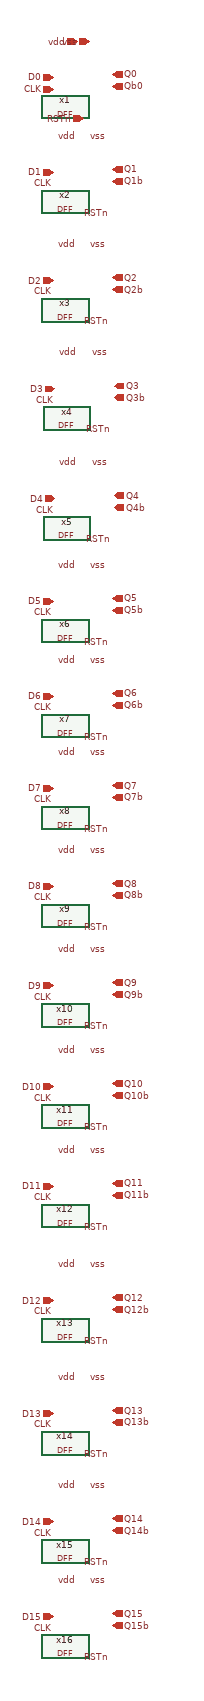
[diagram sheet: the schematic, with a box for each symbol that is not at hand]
v {xschem version=3.4.7 file_version=1.2}
G {}
K {}
V {}
S {}
E {}
C {schematics/PC/DFF/DFF.sym} 0 20 0 0 {name=x1}
C {schematics/PC/DFF/DFF.sym} 0 180 0 0 {name=x2}
C {iopin.sym} 20 -90 3 0 {name=p9 lab=vdd}
C {lab_wire.sym} 40 70 2 0 {name=p35 sig_type=std_logic lab=vss}
C {iopin.sym} 40 -90 3 0 {name=p19 lab=vss}
C {ipin.sym} 30 40 2 0 {name=p4 lab=RSTn}
C {ipin.sym} -20 -10 0 0 {name=p41 lab=CLK}
C {opin.sym} 80 -35 0 0 {name=p2 lab=Q0}
C {opin.sym} 80 -15 0 0 {name=p1 lab=Qb0}
C {ipin.sym} -20 -30 0 0 {name=p3 lab=D0}
C {opin.sym} 80 125 0 0 {name=p5 lab=Q1}
C {opin.sym} 80 145 0 0 {name=p6 lab=Q1b}
C {ipin.sym} -20 130 0 0 {name=p7 lab=D1}
C {lab_wire.sym} -20 150 0 0 {name=p11 sig_type=std_logic lab=CLK}
C {lab_wire.sym} 20 70 0 0 {name=p8 sig_type=std_logic lab=vdd}
C {lab_wire.sym} 30 200 2 0 {name=p10 sig_type=std_logic lab=RSTn}
C {schematics/PC/DFF/DFF.sym} 0 362.5 0 0 {name=x3}
C {lab_wire.sym} 40 252.5 2 0 {name=p12 sig_type=std_logic lab=vss}
C {opin.sym} 80 307.5 0 0 {name=p13 lab=Q2}
C {opin.sym} 80 327.5 0 0 {name=p14 lab=Q2b}
C {ipin.sym} -20 312.5 0 0 {name=p15 lab=D2}
C {lab_wire.sym} -20 332.5 0 0 {name=p16 sig_type=std_logic lab=CLK}
C {lab_wire.sym} 20 252.5 0 0 {name=p17 sig_type=std_logic lab=vdd}
C {lab_wire.sym} 30 382.5 2 0 {name=p18 sig_type=std_logic lab=RSTn}
C {schematics/PC/DFF/DFF.sym} 2.5 545 0 0 {name=x4}
C {lab_wire.sym} 42.5 435 2 0 {name=p20 sig_type=std_logic lab=vss}
C {opin.sym} 82.5 490 0 0 {name=p21 lab=Q3}
C {opin.sym} 82.5 510 0 0 {name=p22 lab=Q3b}
C {ipin.sym} -17.5 495 0 0 {name=p23 lab=D3}
C {lab_wire.sym} -17.5 515 0 0 {name=p24 sig_type=std_logic lab=CLK}
C {lab_wire.sym} 22.5 435 0 0 {name=p25 sig_type=std_logic lab=vdd}
C {lab_wire.sym} 32.5 565 2 0 {name=p26 sig_type=std_logic lab=RSTn}
C {schematics/PC/DFF/DFF.sym} 2.5 730 0 0 {name=x5}
C {lab_wire.sym} 42.5 620 2 0 {name=p27 sig_type=std_logic lab=vss}
C {opin.sym} 82.5 675 0 0 {name=p28 lab=Q4}
C {opin.sym} 82.5 695 0 0 {name=p29 lab=Q4b}
C {ipin.sym} -17.5 680 0 0 {name=p30 lab=D4}
C {lab_wire.sym} -17.5 700 0 0 {name=p31 sig_type=std_logic lab=CLK}
C {lab_wire.sym} 22.5 620 0 0 {name=p32 sig_type=std_logic lab=vdd}
C {lab_wire.sym} 32.5 750 2 0 {name=p33 sig_type=std_logic lab=RSTn}
C {schematics/PC/DFF/DFF.sym} 0 902.5 0 0 {name=x6}
C {lab_wire.sym} 40 792.5 2 0 {name=p34 sig_type=std_logic lab=vss}
C {opin.sym} 80 847.5 0 0 {name=p36 lab=Q5}
C {opin.sym} 80 867.5 0 0 {name=p37 lab=Q5b}
C {ipin.sym} -20 852.5 0 0 {name=p38 lab=D5}
C {lab_wire.sym} -20 872.5 0 0 {name=p39 sig_type=std_logic lab=CLK}
C {lab_wire.sym} 20 792.5 0 0 {name=p40 sig_type=std_logic lab=vdd}
C {lab_wire.sym} 30 922.5 2 0 {name=p42 sig_type=std_logic lab=RSTn}
C {schematics/PC/DFF/DFF.sym} 0 1062.5 0 0 {name=x7}
C {lab_wire.sym} 40 952.5 2 0 {name=p43 sig_type=std_logic lab=vss}
C {opin.sym} 80 1007.5 0 0 {name=p44 lab=Q6}
C {opin.sym} 80 1027.5 0 0 {name=p45 lab=Q6b}
C {ipin.sym} -20 1012.5 0 0 {name=p46 lab=D6}
C {lab_wire.sym} -20 1032.5 0 0 {name=p47 sig_type=std_logic lab=CLK}
C {lab_wire.sym} 20 952.5 0 0 {name=p48 sig_type=std_logic lab=vdd}
C {lab_wire.sym} 30 1082.5 2 0 {name=p49 sig_type=std_logic lab=RSTn}
C {schematics/PC/DFF/DFF.sym} 0 1217.5 0 0 {name=x8}
C {lab_wire.sym} 40 1107.5 2 0 {name=p50 sig_type=std_logic lab=vss}
C {opin.sym} 80 1162.5 0 0 {name=p51 lab=Q7}
C {opin.sym} 80 1182.5 0 0 {name=p52 lab=Q7b}
C {ipin.sym} -20 1167.5 0 0 {name=p53 lab=D7}
C {lab_wire.sym} -20 1187.5 0 0 {name=p54 sig_type=std_logic lab=CLK}
C {lab_wire.sym} 20 1107.5 0 0 {name=p55 sig_type=std_logic lab=vdd}
C {lab_wire.sym} 30 1237.5 2 0 {name=p56 sig_type=std_logic lab=RSTn}
C {schematics/PC/DFF/DFF.sym} 0 1382.5 0 0 {name=x9}
C {lab_wire.sym} 40 1272.5 2 0 {name=p57 sig_type=std_logic lab=vss}
C {opin.sym} 80 1327.5 0 0 {name=p58 lab=Q8}
C {opin.sym} 80 1347.5 0 0 {name=p59 lab=Q8b}
C {ipin.sym} -20 1332.5 0 0 {name=p60 lab=D8}
C {lab_wire.sym} -20 1352.5 0 0 {name=p61 sig_type=std_logic lab=CLK}
C {lab_wire.sym} 20 1272.5 0 0 {name=p62 sig_type=std_logic lab=vdd}
C {lab_wire.sym} 30 1402.5 2 0 {name=p63 sig_type=std_logic lab=RSTn}
C {schematics/PC/DFF/DFF.sym} 0 1550 0 0 {name=x10}
C {lab_wire.sym} 40 1440 2 0 {name=p64 sig_type=std_logic lab=vss}
C {opin.sym} 80 1495 0 0 {name=p65 lab=Q9}
C {opin.sym} 80 1515 0 0 {name=p66 lab=Q9b}
C {ipin.sym} -20 1500 0 0 {name=p67 lab=D9}
C {lab_wire.sym} -20 1520 0 0 {name=p68 sig_type=std_logic lab=CLK}
C {lab_wire.sym} 20 1440 0 0 {name=p69 sig_type=std_logic lab=vdd}
C {lab_wire.sym} 30 1570 2 0 {name=p70 sig_type=std_logic lab=RSTn}
C {schematics/PC/DFF/DFF.sym} 0 1720 0 0 {name=x11}
C {lab_wire.sym} 40 1610 2 0 {name=p71 sig_type=std_logic lab=vss}
C {opin.sym} 80 1665 0 0 {name=p72 lab=Q10}
C {opin.sym} 80 1685 0 0 {name=p73 lab=Q10b}
C {ipin.sym} -20 1670 0 0 {name=p74 lab=D10}
C {lab_wire.sym} -20 1690 0 0 {name=p75 sig_type=std_logic lab=CLK}
C {lab_wire.sym} 20 1610 0 0 {name=p76 sig_type=std_logic lab=vdd}
C {lab_wire.sym} 30 1740 2 0 {name=p77 sig_type=std_logic lab=RSTn}
C {schematics/PC/DFF/DFF.sym} 0 1887.5 0 0 {name=x12}
C {lab_wire.sym} 40 1777.5 2 0 {name=p78 sig_type=std_logic lab=vss}
C {opin.sym} 80 1832.5 0 0 {name=p79 lab=Q11}
C {opin.sym} 80 1852.5 0 0 {name=p80 lab=Q11b}
C {ipin.sym} -20 1837.5 0 0 {name=p81 lab=D11}
C {lab_wire.sym} -20 1857.5 0 0 {name=p82 sig_type=std_logic lab=CLK}
C {lab_wire.sym} 20 1777.5 0 0 {name=p83 sig_type=std_logic lab=vdd}
C {lab_wire.sym} 30 1907.5 2 0 {name=p84 sig_type=std_logic lab=RSTn}
C {schematics/PC/DFF/DFF.sym} 0 2080 0 0 {name=x13}
C {lab_wire.sym} 40 1970 2 0 {name=p85 sig_type=std_logic lab=vss}
C {opin.sym} 80 2025 0 0 {name=p86 lab=Q12}
C {opin.sym} 80 2045 0 0 {name=p87 lab=Q12b}
C {ipin.sym} -20 2030 0 0 {name=p88 lab=D12}
C {lab_wire.sym} -20 2050 0 0 {name=p89 sig_type=std_logic lab=CLK}
C {lab_wire.sym} 20 1970 0 0 {name=p90 sig_type=std_logic lab=vdd}
C {lab_wire.sym} 30 2100 2 0 {name=p91 sig_type=std_logic lab=RSTn}
C {schematics/PC/DFF/DFF.sym} 0 2270 0 0 {name=x14}
C {lab_wire.sym} 40 2160 2 0 {name=p92 sig_type=std_logic lab=vss}
C {opin.sym} 80 2215 0 0 {name=p93 lab=Q13}
C {opin.sym} 80 2235 0 0 {name=p94 lab=Q13b}
C {ipin.sym} -20 2220 0 0 {name=p95 lab=D13}
C {lab_wire.sym} -20 2240 0 0 {name=p96 sig_type=std_logic lab=CLK}
C {lab_wire.sym} 20 2160 0 0 {name=p97 sig_type=std_logic lab=vdd}
C {lab_wire.sym} 30 2290 2 0 {name=p98 sig_type=std_logic lab=RSTn}
C {schematics/PC/DFF/DFF.sym} 0 2452.5 0 0 {name=x15}
C {lab_wire.sym} 40 2342.5 2 0 {name=p99 sig_type=std_logic lab=vss}
C {opin.sym} 80 2397.5 0 0 {name=p100 lab=Q14}
C {opin.sym} 80 2417.5 0 0 {name=p101 lab=Q14b}
C {ipin.sym} -20 2402.5 0 0 {name=p102 lab=D14}
C {lab_wire.sym} -20 2422.5 0 0 {name=p103 sig_type=std_logic lab=CLK}
C {lab_wire.sym} 20 2342.5 0 0 {name=p104 sig_type=std_logic lab=vdd}
C {lab_wire.sym} 30 2472.5 2 0 {name=p105 sig_type=std_logic lab=RSTn}
C {schematics/PC/DFF/DFF.sym} 0 2612.5 0 0 {name=x16}
C {lab_wire.sym} 40 2502.5 2 0 {name=p106 sig_type=std_logic lab=vss}
C {opin.sym} 80 2557.5 0 0 {name=p107 lab=Q15}
C {opin.sym} 80 2577.5 0 0 {name=p108 lab=Q15b}
C {ipin.sym} -20 2562.5 0 0 {name=p109 lab=D15}
C {lab_wire.sym} -20 2582.5 0 0 {name=p110 sig_type=std_logic lab=CLK}
C {lab_wire.sym} 20 2502.5 0 0 {name=p111 sig_type=std_logic lab=vdd}
C {lab_wire.sym} 30 2632.5 2 0 {name=p112 sig_type=std_logic lab=RSTn}
